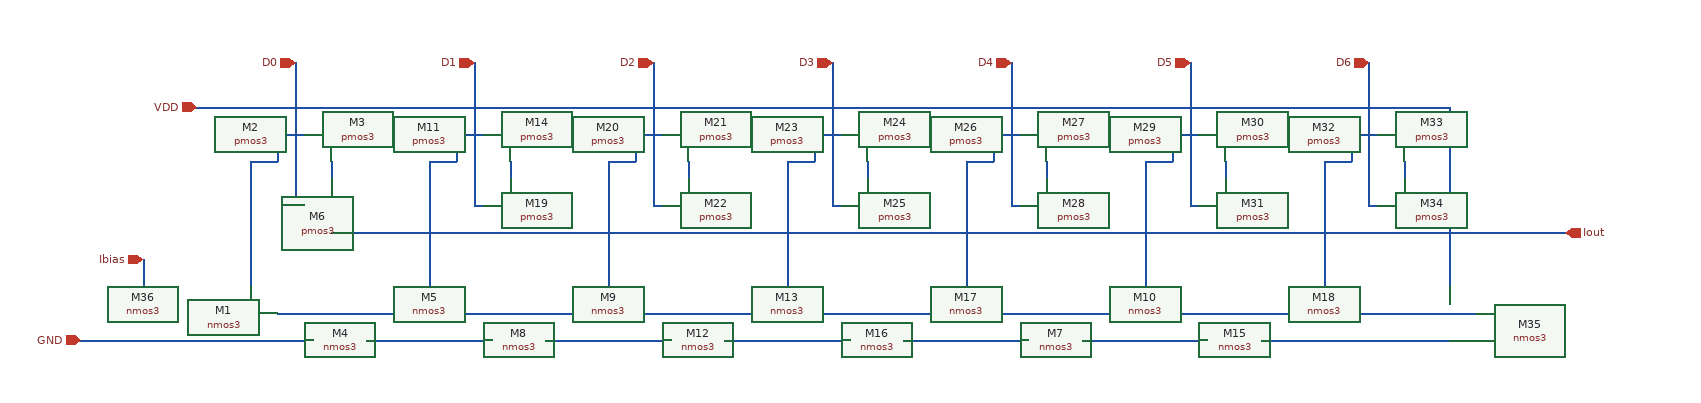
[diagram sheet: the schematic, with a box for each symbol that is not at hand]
v {xschem version=3.4.3 file_version=1.2
}
G {}
K {}
V {}
S {}
E {}
N 0 30 70 30 {
lab=GND}
N 130 30 270 30 {
lab=#net1}
N 330 30 470 30 {
lab=#net2}
N 530 30 670 30 {
lab=#net3}
N 730 30 870 30 {
lab=#net4}
N 930 30 1070 30 {
lab=#net5}
N 1130 30 1200 30 {
lab=#net6}
N 30 0 1230 -0 {
lab=#net7}
N 0 -170 0 -30 {
lab=#net8}
N 0 -170 30 -170 {
lab=#net8}
N 30 -200 30 -170 {
lab=#net8}
N 30 -200 60 -200 {
lab=#net8}
N 90 -170 90 -150 {
lab=#net9}
N -0 -230 1090 -230 {
lab=VDD}
N 200 -170 200 -30 {
lab=#net10}
N 200 -170 230 -170 {
lab=#net10}
N 230 -200 230 -170 {
lab=#net10}
N 230 -200 260 -200 {
lab=#net10}
N 290 -170 290 -150 {
lab=#net11}
N 400 -170 400 -30 {
lab=#net12}
N 400 -170 430 -170 {
lab=#net12}
N 430 -200 430 -170 {
lab=#net12}
N 430 -200 460 -200 {
lab=#net12}
N 490 -170 490 -150 {
lab=#net13}
N 600 -170 600 -30 {
lab=#net14}
N 600 -170 630 -170 {
lab=#net14}
N 630 -200 630 -170 {
lab=#net14}
N 630 -200 660 -200 {
lab=#net14}
N 690 -170 690 -150 {
lab=#net15}
N 800 -170 800 -30 {
lab=#net16}
N 800 -170 830 -170 {
lab=#net16}
N 830 -200 830 -170 {
lab=#net16}
N 830 -200 860 -200 {
lab=#net16}
N 890 -170 890 -150 {
lab=#net17}
N 1000 -170 1000 -30 {
lab=#net18}
N 1000 -170 1030 -170 {
lab=#net18}
N 1030 -200 1030 -170 {
lab=#net18}
N 1030 -200 1060 -200 {
lab=#net18}
N 1090 -170 1090 -150 {
lab=#net19}
N 90 -90 1090 -90 {
lab=Iout}
N 1200 -170 1230 -170 {
lab=#net20}
N 1230 -200 1230 -170 {
lab=#net20}
N 1230 -200 1260 -200 {
lab=#net20}
N 1290 -170 1290 -150 {
lab=#net21}
N 1200 -170 1200 -30 {
lab=#net20}
N 1200 30 1340 30 {
lab=#net6}
N -120 30 -0 30 {
lab=GND}
N 1090 -90 1290 -90 {
lab=Iout}
N 1090 -230 1290 -230 {
lab=VDD}
N 1290 -230 1340 -230 {
lab=VDD}
N 1340 -230 1340 -30 {
lab=VDD}
N 1230 0 1370 -0 {
lab=#net7}
N 50 -120 60 -120 {
lab=D0}
N 50 -280 50 -120 {
lab=D0}
N 250 -120 260 -120 {
lab=D1}
N 250 -280 250 -120 {
lab=D1}
N 450 -120 460 -120 {
lab=D2}
N 450 -280 450 -120 {
lab=D2}
N 650 -120 660 -120 {
lab=D3}
N 650 -280 650 -120 {
lab=D3}
N 850 -120 860 -120 {
lab=D4}
N 850 -280 850 -120 {
lab=D4}
N 1050 -120 1060 -120 {
lab=D5}
N 1050 -280 1050 -120 {
lab=D5}
N 1250 -120 1260 -120 {
lab=D0}
N 1250 -280 1250 -120 {
lab=D0}
N 1290 -90 1470 -90 {
lab=Iout}
N -60 -230 -0 -230 {
lab=VDD}
N -190 30 -120 30 {
lab=GND}
N -120 -60 -120 -30 {
lab=Ibias}
C {madvlsi/nmos3.sym} 0 0 0 1 {name=M1
L=0.15
W=1
body=GND
nf=1
mult=2
ad="'int((nf+1)/2) * W/nf * 0.29'" 
pd="'2*int((nf+1)/2) * (W/nf + 0.29)'"
as="'int((nf+2)/2) * W/nf * 0.29'" 
ps="'2*int((nf+2)/2) * (W/nf + 0.29)'"
nrd="'0.29 / W'" nrs="'0.29 / W'"
sa=0 sb=0 sd=0
model=nfet_01v8
spiceprefix=X
}
C {madvlsi/nmos3.sym} 100 30 3 1 {name=M4
L=0.15
W=1
body=GND
nf=1
mult=2
ad="'int((nf+1)/2) * W/nf * 0.29'" 
pd="'2*int((nf+1)/2) * (W/nf + 0.29)'"
as="'int((nf+2)/2) * W/nf * 0.29'" 
ps="'2*int((nf+2)/2) * (W/nf + 0.29)'"
nrd="'0.29 / W'" nrs="'0.29 / W'"
sa=0 sb=0 sd=0
model=nfet_01v8
spiceprefix=X
}
C {madvlsi/nmos3.sym} 200 0 0 1 {name=M5
L=0.15
W=1
body=GND
nf=1
mult=1
ad="'int((nf+1)/2) * W/nf * 0.29'" 
pd="'2*int((nf+1)/2) * (W/nf + 0.29)'"
as="'int((nf+2)/2) * W/nf * 0.29'" 
ps="'2*int((nf+2)/2) * (W/nf + 0.29)'"
nrd="'0.29 / W'" nrs="'0.29 / W'"
sa=0 sb=0 sd=0
model=nfet_01v8
spiceprefix=X
}
C {madvlsi/nmos3.sym} 300 30 3 1 {name=M8
L=0.15
W=1
body=GND
nf=1
mult=2
ad="'int((nf+1)/2) * W/nf * 0.29'" 
pd="'2*int((nf+1)/2) * (W/nf + 0.29)'"
as="'int((nf+2)/2) * W/nf * 0.29'" 
ps="'2*int((nf+2)/2) * (W/nf + 0.29)'"
nrd="'0.29 / W'" nrs="'0.29 / W'"
sa=0 sb=0 sd=0
model=nfet_01v8
spiceprefix=X
}
C {madvlsi/nmos3.sym} 400 0 0 1 {name=M9
L=0.15
W=1
body=GND
nf=1
mult=1
ad="'int((nf+1)/2) * W/nf * 0.29'" 
pd="'2*int((nf+1)/2) * (W/nf + 0.29)'"
as="'int((nf+2)/2) * W/nf * 0.29'" 
ps="'2*int((nf+2)/2) * (W/nf + 0.29)'"
nrd="'0.29 / W'" nrs="'0.29 / W'"
sa=0 sb=0 sd=0
model=nfet_01v8
spiceprefix=X
}
C {madvlsi/nmos3.sym} 500 30 3 1 {name=M12
L=0.15
W=1
body=GND
nf=1
mult=2
ad="'int((nf+1)/2) * W/nf * 0.29'" 
pd="'2*int((nf+1)/2) * (W/nf + 0.29)'"
as="'int((nf+2)/2) * W/nf * 0.29'" 
ps="'2*int((nf+2)/2) * (W/nf + 0.29)'"
nrd="'0.29 / W'" nrs="'0.29 / W'"
sa=0 sb=0 sd=0
model=nfet_01v8
spiceprefix=X
}
C {madvlsi/nmos3.sym} 600 0 0 1 {name=M13
L=0.15
W=1
body=GND
nf=1
mult=1
ad="'int((nf+1)/2) * W/nf * 0.29'" 
pd="'2*int((nf+1)/2) * (W/nf + 0.29)'"
as="'int((nf+2)/2) * W/nf * 0.29'" 
ps="'2*int((nf+2)/2) * (W/nf + 0.29)'"
nrd="'0.29 / W'" nrs="'0.29 / W'"
sa=0 sb=0 sd=0
model=nfet_01v8
spiceprefix=X
}
C {madvlsi/nmos3.sym} 700 30 3 1 {name=M16
L=0.15
W=1
body=GND
nf=1
mult=2
ad="'int((nf+1)/2) * W/nf * 0.29'" 
pd="'2*int((nf+1)/2) * (W/nf + 0.29)'"
as="'int((nf+2)/2) * W/nf * 0.29'" 
ps="'2*int((nf+2)/2) * (W/nf + 0.29)'"
nrd="'0.29 / W'" nrs="'0.29 / W'"
sa=0 sb=0 sd=0
model=nfet_01v8
spiceprefix=X
}
C {madvlsi/nmos3.sym} 800 0 0 1 {name=M17
L=0.15
W=1
body=GND
nf=1
mult=1
ad="'int((nf+1)/2) * W/nf * 0.29'" 
pd="'2*int((nf+1)/2) * (W/nf + 0.29)'"
as="'int((nf+2)/2) * W/nf * 0.29'" 
ps="'2*int((nf+2)/2) * (W/nf + 0.29)'"
nrd="'0.29 / W'" nrs="'0.29 / W'"
sa=0 sb=0 sd=0
model=nfet_01v8
spiceprefix=X
}
C {madvlsi/nmos3.sym} 900 30 3 1 {name=M7
L=0.15
W=1
body=GND
nf=1
mult=2
ad="'int((nf+1)/2) * W/nf * 0.29'" 
pd="'2*int((nf+1)/2) * (W/nf + 0.29)'"
as="'int((nf+2)/2) * W/nf * 0.29'" 
ps="'2*int((nf+2)/2) * (W/nf + 0.29)'"
nrd="'0.29 / W'" nrs="'0.29 / W'"
sa=0 sb=0 sd=0
model=nfet_01v8
spiceprefix=X
}
C {madvlsi/nmos3.sym} 1000 0 0 1 {name=M10
L=0.15
W=1
body=GND
nf=1
mult=1
ad="'int((nf+1)/2) * W/nf * 0.29'" 
pd="'2*int((nf+1)/2) * (W/nf + 0.29)'"
as="'int((nf+2)/2) * W/nf * 0.29'" 
ps="'2*int((nf+2)/2) * (W/nf + 0.29)'"
nrd="'0.29 / W'" nrs="'0.29 / W'"
sa=0 sb=0 sd=0
model=nfet_01v8
spiceprefix=X
}
C {madvlsi/nmos3.sym} 1100 30 3 1 {name=M15
L=0.15
W=1
body=GND
nf=1
mult=2
ad="'int((nf+1)/2) * W/nf * 0.29'" 
pd="'2*int((nf+1)/2) * (W/nf + 0.29)'"
as="'int((nf+2)/2) * W/nf * 0.29'" 
ps="'2*int((nf+2)/2) * (W/nf + 0.29)'"
nrd="'0.29 / W'" nrs="'0.29 / W'"
sa=0 sb=0 sd=0
model=nfet_01v8
spiceprefix=X
}
C {madvlsi/nmos3.sym} 1200 0 0 1 {name=M18
L=0.15
W=1
body=GND
nf=1
mult=1
ad="'int((nf+1)/2) * W/nf * 0.29'" 
pd="'2*int((nf+1)/2) * (W/nf + 0.29)'"
as="'int((nf+2)/2) * W/nf * 0.29'" 
ps="'2*int((nf+2)/2) * (W/nf + 0.29)'"
nrd="'0.29 / W'" nrs="'0.29 / W'"
sa=0 sb=0 sd=0
model=nfet_01v8
spiceprefix=X
}
C {madvlsi/pmos3.sym} 0 -200 0 1 {name=M2
L=0.15
W=1
body=VDD
nf=1
mult=1
ad="'int((nf+1)/2) * W/nf * 0.29'" 
pd="'2*int((nf+1)/2) * (W/nf + 0.29)'"
as="'int((nf+2)/2) * W/nf * 0.29'" 
ps="'2*int((nf+2)/2) * (W/nf + 0.29)'"
nrd="'0.29 / W'" nrs="'0.29 / W'"
sa=0 sb=0 sd=0
model=pfet_01v8
spiceprefix=X
}
C {madvlsi/pmos3.sym} 90 -200 0 0 {name=M3
L=0.15
W=1
body=VDD
nf=1
mult=1
ad="'int((nf+1)/2) * W/nf * 0.29'" 
pd="'2*int((nf+1)/2) * (W/nf + 0.29)'"
as="'int((nf+2)/2) * W/nf * 0.29'" 
ps="'2*int((nf+2)/2) * (W/nf + 0.29)'"
nrd="'0.29 / W'" nrs="'0.29 / W'"
sa=0 sb=0 sd=0
model=pfet_01v8
spiceprefix=X
}
C {madvlsi/pmos3.sym} 90 -120 0 0 {name=M6
L=0.15
W=1
body=VDD
nf=1
mult=1
ad="'int((nf+1)/2) * W/nf * 0.29'" 
pd="'2*int((nf+1)/2) * (W/nf + 0.29)'"
as="'int((nf+2)/2) * W/nf * 0.29'" 
ps="'2*int((nf+2)/2) * (W/nf + 0.29)'"
nrd="'0.29 / W'" nrs="'0.29 / W'"
sa=0 sb=0 sd=0
model=pfet_01v8
spiceprefix=X
}
C {madvlsi/pmos3.sym} 200 -200 0 1 {name=M11
L=0.15
W=1
body=VDD
nf=1
mult=1
ad="'int((nf+1)/2) * W/nf * 0.29'" 
pd="'2*int((nf+1)/2) * (W/nf + 0.29)'"
as="'int((nf+2)/2) * W/nf * 0.29'" 
ps="'2*int((nf+2)/2) * (W/nf + 0.29)'"
nrd="'0.29 / W'" nrs="'0.29 / W'"
sa=0 sb=0 sd=0
model=pfet_01v8
spiceprefix=X
}
C {madvlsi/pmos3.sym} 290 -200 0 0 {name=M14
L=0.15
W=1
body=VDD
nf=1
mult=1
ad="'int((nf+1)/2) * W/nf * 0.29'" 
pd="'2*int((nf+1)/2) * (W/nf + 0.29)'"
as="'int((nf+2)/2) * W/nf * 0.29'" 
ps="'2*int((nf+2)/2) * (W/nf + 0.29)'"
nrd="'0.29 / W'" nrs="'0.29 / W'"
sa=0 sb=0 sd=0
model=pfet_01v8
spiceprefix=X
}
C {madvlsi/pmos3.sym} 290 -120 0 0 {name=M19
L=0.15
W=1
body=VDD
nf=1
mult=1
ad="'int((nf+1)/2) * W/nf * 0.29'" 
pd="'2*int((nf+1)/2) * (W/nf + 0.29)'"
as="'int((nf+2)/2) * W/nf * 0.29'" 
ps="'2*int((nf+2)/2) * (W/nf + 0.29)'"
nrd="'0.29 / W'" nrs="'0.29 / W'"
sa=0 sb=0 sd=0
model=pfet_01v8
spiceprefix=X
}
C {madvlsi/pmos3.sym} 400 -200 0 1 {name=M20
L=0.15
W=1
body=VDD
nf=1
mult=1
ad="'int((nf+1)/2) * W/nf * 0.29'" 
pd="'2*int((nf+1)/2) * (W/nf + 0.29)'"
as="'int((nf+2)/2) * W/nf * 0.29'" 
ps="'2*int((nf+2)/2) * (W/nf + 0.29)'"
nrd="'0.29 / W'" nrs="'0.29 / W'"
sa=0 sb=0 sd=0
model=pfet_01v8
spiceprefix=X
}
C {madvlsi/pmos3.sym} 490 -200 0 0 {name=M21
L=0.15
W=1
body=VDD
nf=1
mult=1
ad="'int((nf+1)/2) * W/nf * 0.29'" 
pd="'2*int((nf+1)/2) * (W/nf + 0.29)'"
as="'int((nf+2)/2) * W/nf * 0.29'" 
ps="'2*int((nf+2)/2) * (W/nf + 0.29)'"
nrd="'0.29 / W'" nrs="'0.29 / W'"
sa=0 sb=0 sd=0
model=pfet_01v8
spiceprefix=X
}
C {madvlsi/pmos3.sym} 490 -120 0 0 {name=M22
L=0.15
W=1
body=VDD
nf=1
mult=1
ad="'int((nf+1)/2) * W/nf * 0.29'" 
pd="'2*int((nf+1)/2) * (W/nf + 0.29)'"
as="'int((nf+2)/2) * W/nf * 0.29'" 
ps="'2*int((nf+2)/2) * (W/nf + 0.29)'"
nrd="'0.29 / W'" nrs="'0.29 / W'"
sa=0 sb=0 sd=0
model=pfet_01v8
spiceprefix=X
}
C {madvlsi/pmos3.sym} 600 -200 0 1 {name=M23
L=0.15
W=1
body=VDD
nf=1
mult=1
ad="'int((nf+1)/2) * W/nf * 0.29'" 
pd="'2*int((nf+1)/2) * (W/nf + 0.29)'"
as="'int((nf+2)/2) * W/nf * 0.29'" 
ps="'2*int((nf+2)/2) * (W/nf + 0.29)'"
nrd="'0.29 / W'" nrs="'0.29 / W'"
sa=0 sb=0 sd=0
model=pfet_01v8
spiceprefix=X
}
C {madvlsi/pmos3.sym} 690 -200 0 0 {name=M24
L=0.15
W=1
body=VDD
nf=1
mult=1
ad="'int((nf+1)/2) * W/nf * 0.29'" 
pd="'2*int((nf+1)/2) * (W/nf + 0.29)'"
as="'int((nf+2)/2) * W/nf * 0.29'" 
ps="'2*int((nf+2)/2) * (W/nf + 0.29)'"
nrd="'0.29 / W'" nrs="'0.29 / W'"
sa=0 sb=0 sd=0
model=pfet_01v8
spiceprefix=X
}
C {madvlsi/pmos3.sym} 690 -120 0 0 {name=M25
L=0.15
W=1
body=VDD
nf=1
mult=1
ad="'int((nf+1)/2) * W/nf * 0.29'" 
pd="'2*int((nf+1)/2) * (W/nf + 0.29)'"
as="'int((nf+2)/2) * W/nf * 0.29'" 
ps="'2*int((nf+2)/2) * (W/nf + 0.29)'"
nrd="'0.29 / W'" nrs="'0.29 / W'"
sa=0 sb=0 sd=0
model=pfet_01v8
spiceprefix=X
}
C {madvlsi/pmos3.sym} 800 -200 0 1 {name=M26
L=0.15
W=1
body=VDD
nf=1
mult=1
ad="'int((nf+1)/2) * W/nf * 0.29'" 
pd="'2*int((nf+1)/2) * (W/nf + 0.29)'"
as="'int((nf+2)/2) * W/nf * 0.29'" 
ps="'2*int((nf+2)/2) * (W/nf + 0.29)'"
nrd="'0.29 / W'" nrs="'0.29 / W'"
sa=0 sb=0 sd=0
model=pfet_01v8
spiceprefix=X
}
C {madvlsi/pmos3.sym} 890 -200 0 0 {name=M27
L=0.15
W=1
body=VDD
nf=1
mult=1
ad="'int((nf+1)/2) * W/nf * 0.29'" 
pd="'2*int((nf+1)/2) * (W/nf + 0.29)'"
as="'int((nf+2)/2) * W/nf * 0.29'" 
ps="'2*int((nf+2)/2) * (W/nf + 0.29)'"
nrd="'0.29 / W'" nrs="'0.29 / W'"
sa=0 sb=0 sd=0
model=pfet_01v8
spiceprefix=X
}
C {madvlsi/pmos3.sym} 890 -120 0 0 {name=M28
L=0.15
W=1
body=VDD
nf=1
mult=1
ad="'int((nf+1)/2) * W/nf * 0.29'" 
pd="'2*int((nf+1)/2) * (W/nf + 0.29)'"
as="'int((nf+2)/2) * W/nf * 0.29'" 
ps="'2*int((nf+2)/2) * (W/nf + 0.29)'"
nrd="'0.29 / W'" nrs="'0.29 / W'"
sa=0 sb=0 sd=0
model=pfet_01v8
spiceprefix=X
}
C {madvlsi/pmos3.sym} 1000 -200 0 1 {name=M29
L=0.15
W=1
body=VDD
nf=1
mult=1
ad="'int((nf+1)/2) * W/nf * 0.29'" 
pd="'2*int((nf+1)/2) * (W/nf + 0.29)'"
as="'int((nf+2)/2) * W/nf * 0.29'" 
ps="'2*int((nf+2)/2) * (W/nf + 0.29)'"
nrd="'0.29 / W'" nrs="'0.29 / W'"
sa=0 sb=0 sd=0
model=pfet_01v8
spiceprefix=X
}
C {madvlsi/pmos3.sym} 1090 -200 0 0 {name=M30
L=0.15
W=1
body=VDD
nf=1
mult=1
ad="'int((nf+1)/2) * W/nf * 0.29'" 
pd="'2*int((nf+1)/2) * (W/nf + 0.29)'"
as="'int((nf+2)/2) * W/nf * 0.29'" 
ps="'2*int((nf+2)/2) * (W/nf + 0.29)'"
nrd="'0.29 / W'" nrs="'0.29 / W'"
sa=0 sb=0 sd=0
model=pfet_01v8
spiceprefix=X
}
C {madvlsi/pmos3.sym} 1090 -120 0 0 {name=M31
L=0.15
W=1
body=VDD
nf=1
mult=1
ad="'int((nf+1)/2) * W/nf * 0.29'" 
pd="'2*int((nf+1)/2) * (W/nf + 0.29)'"
as="'int((nf+2)/2) * W/nf * 0.29'" 
ps="'2*int((nf+2)/2) * (W/nf + 0.29)'"
nrd="'0.29 / W'" nrs="'0.29 / W'"
sa=0 sb=0 sd=0
model=pfet_01v8
spiceprefix=X
}
C {madvlsi/pmos3.sym} 1200 -200 0 1 {name=M32
L=0.15
W=1
body=VDD
nf=1
mult=1
ad="'int((nf+1)/2) * W/nf * 0.29'" 
pd="'2*int((nf+1)/2) * (W/nf + 0.29)'"
as="'int((nf+2)/2) * W/nf * 0.29'" 
ps="'2*int((nf+2)/2) * (W/nf + 0.29)'"
nrd="'0.29 / W'" nrs="'0.29 / W'"
sa=0 sb=0 sd=0
model=pfet_01v8
spiceprefix=X
}
C {madvlsi/pmos3.sym} 1290 -200 0 0 {name=M33
L=0.15
W=1
body=VDD
nf=1
mult=1
ad="'int((nf+1)/2) * W/nf * 0.29'" 
pd="'2*int((nf+1)/2) * (W/nf + 0.29)'"
as="'int((nf+2)/2) * W/nf * 0.29'" 
ps="'2*int((nf+2)/2) * (W/nf + 0.29)'"
nrd="'0.29 / W'" nrs="'0.29 / W'"
sa=0 sb=0 sd=0
model=pfet_01v8
spiceprefix=X
}
C {madvlsi/pmos3.sym} 1290 -120 0 0 {name=M34
L=0.15
W=1
body=VDD
nf=1
mult=1
ad="'int((nf+1)/2) * W/nf * 0.29'" 
pd="'2*int((nf+1)/2) * (W/nf + 0.29)'"
as="'int((nf+2)/2) * W/nf * 0.29'" 
ps="'2*int((nf+2)/2) * (W/nf + 0.29)'"
nrd="'0.29 / W'" nrs="'0.29 / W'"
sa=0 sb=0 sd=0
model=pfet_01v8
spiceprefix=X
}
C {madvlsi/nmos3.sym} 1340 0 0 1 {name=M35
L=0.15
W=1
body=GND
nf=1
mult=1
ad="'int((nf+1)/2) * W/nf * 0.29'" 
pd="'2*int((nf+1)/2) * (W/nf + 0.29)'"
as="'int((nf+2)/2) * W/nf * 0.29'" 
ps="'2*int((nf+2)/2) * (W/nf + 0.29)'"
nrd="'0.29 / W'" nrs="'0.29 / W'"
sa=0 sb=0 sd=0
model=nfet_01v8
spiceprefix=X
}
C {madvlsi/nmos3.sym} -120 0 0 1 {name=M36
L=0.15
W=1
body=GND
nf=1
mult=2
ad="'int((nf+1)/2) * W/nf * 0.29'" 
pd="'2*int((nf+1)/2) * (W/nf + 0.29)'"
as="'int((nf+2)/2) * W/nf * 0.29'" 
ps="'2*int((nf+2)/2) * (W/nf + 0.29)'"
nrd="'0.29 / W'" nrs="'0.29 / W'"
sa=0 sb=0 sd=0
model=nfet_01v8
spiceprefix=X
}
C {devices/iopin.sym} -60 -230 2 0 {name=p1 lab=VDD}
C {devices/iopin.sym} -190 30 2 0 {name=p2 lab=GND}
C {devices/iopin.sym} -120 -60 2 0 {name=p3 lab=Ibias}
C {devices/opin.sym} 1470 -90 0 0 {name=p4 lab=Iout}
C {devices/ipin.sym} 50 -280 1 0 {name=p5 lab=D0}
C {devices/ipin.sym} 250 -280 1 0 {name=p6 lab=D1}
C {devices/ipin.sym} 450 -280 1 0 {name=p7 lab=D2}
C {devices/ipin.sym} 650 -280 1 0 {name=p8 lab=D3}
C {devices/ipin.sym} 850 -280 1 0 {name=p9 lab=D4}
C {devices/ipin.sym} 1050 -280 1 0 {name=p10 lab=D5}
C {devices/ipin.sym} 1250 -280 1 0 {name=p11 lab=D6}
